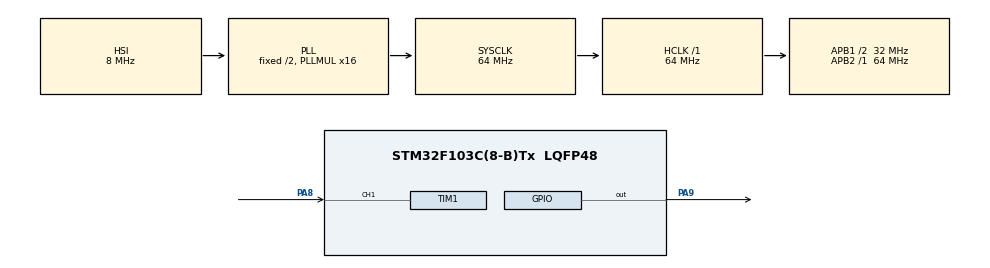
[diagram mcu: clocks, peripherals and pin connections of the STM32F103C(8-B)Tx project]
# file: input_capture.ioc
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Mcu.Family=STM32F1
Mcu.Name=STM32F103C(8-B)Tx
Mcu.Package=LQFP48
NVIC.PriorityGroup=NVIC_PRIORITYGROUP_4
NVIC.TIM1_CC_IRQn=true\:3\:0\:true\:false\:true\:true\:true\:true
PA13.Mode=Serial_Wire
PA13.Signal=SYS_JTMS-SWDIO
PA14.Mode=Serial_Wire
PA14.Signal=SYS_JTCK-SWCLK
PA8.Signal=S_TIM1_CH1
PA9.Signal=GPIO_Output
ProjectManager.HeapSize=0x200
ProjectManager.StackSize=0x400
ProjectManager.TargetToolchain=STM32CubeIDE
RCC.AHBFreq_Value=64000000
RCC.APB1CLKDivider=RCC_HCLK_DIV2
RCC.APB1Freq_Value=32000000
RCC.APB1TimFreq_Value=64000000
RCC.APB2Freq_Value=64000000
RCC.APB2TimFreq_Value=64000000
RCC.HCLKFreq_Value=64000000
RCC.PLLMUL=RCC_PLL_MUL16
RCC.SYSCLKFreq_VALUE=64000000
RCC.SYSCLKSource=RCC_SYSCLKSOURCE_PLLCLK
RCC.USBFreq_Value=64000000
SH.S_TIM1_CH1.0=TIM1_CH1,Input_Capture1_from_TI1
TIM1.Channel-Input_Capture1_from_TI1=TIM_CHANNEL_1
TIM1.Prescaler=63
VP_TIM1_VS_ClockSourceINT.Mode=Internal
board=custom

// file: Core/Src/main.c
/* USER CODE BEGIN Header */
/**
  ******************************************************************************
  * @file           : main.c
  * @brief          : Main program body
  ******************************************************************************
  * @attention
  *
  * Copyright (c) 2026 STMicroelectronics.
  * All rights reserved.
  *
  * This software is licensed under terms that can be found in the LICENSE file
  * in the root directory of this software component.
  * If no LICENSE file comes with this software, it is provided AS-IS.
  *
  ******************************************************************************
  */
/* USER CODE END Header */
#include "main.h"

/* USER CODE BEGIN Includes */
#include "hcsr04.h"
/* USER CODE END Includes */

TIM_HandleTypeDef htim1;

/* USER CODE BEGIN PV */

HCSR04_Cliff_t my_hcsr04_1;
HCSR04_Cliff_t my_hcsr04_2;

volatile float debug_dist_1 = 0.0f;
volatile float debug_dist_2 = 0.0f;
volatile uint8_t filter_1 = 0;
volatile uint8_t filter_2 = 0;

volatile uint8_t flag_cliff_1 = 0;
volatile uint8_t flag_cliff_2 = 0;

uint32_t last_ping_time = 0;
uint8_t current_sensor = 1;

/* USER CODE END PV */

void SystemClock_Config(void);
static void MX_GPIO_Init(void);
static void MX_TIM1_Init(void);

/* USER CODE BEGIN 0 */
void Callback_Sensor1(HCSR04_Cliff_t* dev) {
    flag_cliff_1 = 1;
}

void Callback_Sensor2(HCSR04_Cliff_t* dev) {
    flag_cliff_2 = 1;
}

void HAL_TIM_IC_CaptureCallback(TIM_HandleTypeDef *htim)
{
    if (htim->Instance == TIM1)
    {
        // Truyền thẳng cả 2 vào, code trong hcsr04.c của bạn
        // sẽ tự biết lọc cái nào của CH1, cái nào của CH2
        HCSR04_Cliff_Capture_Callback(&my_hcsr04_1, htim);
        HCSR04_Cliff_Capture_Callback(&my_hcsr04_2, htim);
    }
}

/* USER CODE END 0 */

int main(void)
{

  /* MCU Configuration--------------------------------------------------------*/

  /* Reset of all peripherals, Initializes the Flash interface and the Systick. */
  HAL_Init();

  /* Configure the system clock */
  SystemClock_Config();

  /* Initialize all configured peripherals */
  MX_GPIO_Init();
  MX_TIM1_Init();
  /* USER CODE BEGIN 2 */

  /* QUAN TRỌNG - kiểm tra trong file .ioc:
   *  - Pinout: PA8 phải được gán là TIM1_CH1 (Input Capture direct mode).
   *            ECHO của HC-SR04 phải nối vào PA8, KHÔNG phải PA9.
   *            PA9 chỉ dùng làm chân TRIG (GPIO output).
   *  - NVIC  : tick "TIM1 capture compare interrupt" (TIM1_CC_IRQn).
   * Dòng enable NVIC dưới đây là lớp phòng hộ bằng code, để ngắt vẫn
   * chạy được dù lỡ quên tick trong .ioc. Nhưng việc gán PA8 = TIM1_CH1
   * thì PHẢI làm trong .ioc, code không thay được phần đó. */
  HAL_NVIC_SetPriority(TIM1_CC_IRQn, 0, 0);
  HAL_NVIC_EnableIRQ(TIM1_CC_IRQn);

  /* USER CODE BEGIN 2 */
    // Init Sensor 1 (TRIG = PB0, ECHO = PA8/CH1)
    HCSR04_Cliff_Init(&my_hcsr04_1, GPIOB, GPIO_PIN_0, &htim1, TIM_CHANNEL_1, 10.0f, Callback_Sensor1);

    // Init Sensor 2 (TRIG = PB1, ECHO = PA9/CH2)
    HCSR04_Cliff_Init(&my_hcsr04_2, GPIOB, GPIO_PIN_1, &htim1, TIM_CHANNEL_2, 10.0f, Callback_Sensor2);

    // Tắt LED mặc định ban đầu
    HAL_GPIO_WritePin(GPIOC, GPIO_PIN_13, GPIO_PIN_SET);
    /* USER CODE END 2 */

  /* Infinite loop */
  /* USER CODE BEGIN WHILE */
  while (1)
  {
	  if (HAL_GetTick() - last_ping_time > 50)
	        {
	            if (current_sensor == 1 && my_hcsr04_1.state == HCSR04_IDLE_STATE) {
	                HCSR04_Cliff_Start(&my_hcsr04_1);
	                current_sensor = 2; // Nhường lượt tiếp theo cho con 2
	                last_ping_time = HAL_GetTick();
	            }
	            else if (current_sensor == 2 && my_hcsr04_2.state == HCSR04_IDLE_STATE) {
	                HCSR04_Cliff_Start(&my_hcsr04_2);
	                current_sensor = 1; // Nhường lượt tiếp theo cho con 1
	                last_ping_time = HAL_GetTick();
	            }
	        }

	        // 2. GIÁM SÁT LIÊN TỤC (Xử lý khoảng cách hoặc Timeout)
	        HCSR04_Cliff_Handle(&my_hcsr04_1);
	        HCSR04_Cliff_Handle(&my_hcsr04_2);

	        // 3. CẬP NHẬT BIẾN DEBUG
	        debug_dist_1 = my_hcsr04_1.distance;
	        debug_dist_2 = my_hcsr04_2.distance;
	        filter_1 = my_hcsr04_1.filter_count;
	        filter_2 = my_hcsr04_2.filter_count;

	        // 4. XỬ LÝ CẢNH BÁO LED CHUNG
	        // (Ví dụ: 1 trong 2 con phát hiện hố sâu < 10cm thì bật LED)
	        if (flag_cliff_1 == 1 || flag_cliff_2 == 1)
	        {
	            HAL_GPIO_WritePin(GPIOC, GPIO_PIN_13, GPIO_PIN_RESET); // Bật LED
	            flag_cliff_1 = 0;
	            flag_cliff_2 = 0;
	        }
	        else if (my_hcsr04_1.filter_count == 0 && my_hcsr04_2.filter_count == 0)
	        {
	            HAL_GPIO_WritePin(GPIOC, GPIO_PIN_13, GPIO_PIN_SET); // Tắt LED khi CẢ HAI an toàn
	        }

	        HAL_Delay(1);
    /* USER CODE END WHILE */

  }
}

void SystemClock_Config(void)
{
  RCC_OscInitTypeDef RCC_OscInitStruct = {0};
  RCC_ClkInitTypeDef RCC_ClkInitStruct = {0};

  /** Initializes the RCC Oscillators according to the specified parameters
  * in the RCC_OscInitTypeDef structure.
  */
  RCC_OscInitStruct.OscillatorType = RCC_OSCILLATORTYPE_HSI;
  RCC_OscInitStruct.HSIState = RCC_HSI_ON;
  RCC_OscInitStruct.HSICalibrationValue = RCC_HSICALIBRATION_DEFAULT;
  RCC_OscInitStruct.PLL.PLLState = RCC_PLL_ON;
  RCC_OscInitStruct.PLL.PLLSource = RCC_PLLSOURCE_HSI_DIV2;
  RCC_OscInitStruct.PLL.PLLMUL = RCC_PLL_MUL16;
  if (HAL_RCC_OscConfig(&RCC_OscInitStruct) != HAL_OK)
  {
    Error_Handler();
  }

  /** Initializes the CPU, AHB and APB buses clocks
  */
  RCC_ClkInitStruct.ClockType = RCC_CLOCKTYPE_HCLK|RCC_CLOCKTYPE_SYSCLK
                              |RCC_CLOCKTYPE_PCLK1|RCC_CLOCKTYPE_PCLK2;
  RCC_ClkInitStruct.SYSCLKSource = RCC_SYSCLKSOURCE_PLLCLK;
  RCC_ClkInitStruct.AHBCLKDivider = RCC_SYSCLK_DIV1;
  RCC_ClkInitStruct.APB1CLKDivider = RCC_HCLK_DIV2;
  RCC_ClkInitStruct.APB2CLKDivider = RCC_HCLK_DIV1;

  if (HAL_RCC_ClockConfig(&RCC_ClkInitStruct, FLASH_LATENCY_2) != HAL_OK)
  {
    Error_Handler();
  }
}

static void MX_TIM1_Init(void)
{

  TIM_MasterConfigTypeDef sMasterConfig = {0};
  TIM_IC_InitTypeDef sConfigIC = {0};

  htim1.Instance = TIM1;
  htim1.Init.Prescaler = 63;
  htim1.Init.CounterMode = TIM_COUNTERMODE_UP;
  htim1.Init.Period = 65535;
  htim1.Init.ClockDivision = TIM_CLOCKDIVISION_DIV1;
  htim1.Init.RepetitionCounter = 0;
  htim1.Init.AutoReloadPreload = TIM_AUTORELOAD_PRELOAD_DISABLE;
  if (HAL_TIM_IC_Init(&htim1) != HAL_OK)
  {
    Error_Handler();
  }
  sMasterConfig.MasterOutputTrigger = TIM_TRGO_RESET;
  sMasterConfig.MasterSlaveMode = TIM_MASTERSLAVEMODE_DISABLE;
  if (HAL_TIMEx_MasterConfigSynchronization(&htim1, &sMasterConfig) != HAL_OK)
  {
    Error_Handler();
  }
  sConfigIC.ICPolarity = TIM_INPUTCHANNELPOLARITY_RISING;
  sConfigIC.ICSelection = TIM_ICSELECTION_DIRECTTI;
  sConfigIC.ICPrescaler = TIM_ICPSC_DIV1;
  sConfigIC.ICFilter = 0;
  if (HAL_TIM_IC_ConfigChannel(&htim1, &sConfigIC, TIM_CHANNEL_1) != HAL_OK)
  {
    Error_Handler();
  }
  if (HAL_TIM_IC_ConfigChannel(&htim1, &sConfigIC, TIM_CHANNEL_2) != HAL_OK)
  {
    Error_Handler();
  }

}

static void MX_GPIO_Init(void)
{
  GPIO_InitTypeDef GPIO_InitStruct = {0};

  /* GPIO Ports Clock Enable */
  __HAL_RCC_GPIOC_CLK_ENABLE();
  __HAL_RCC_GPIOB_CLK_ENABLE();
  __HAL_RCC_GPIOA_CLK_ENABLE();

  /*Configure GPIO pin Output Level */
  HAL_GPIO_WritePin(GPIOC, GPIO_PIN_13, GPIO_PIN_RESET);

  /*Configure GPIO pin Output Level */
  HAL_GPIO_WritePin(GPIOB, GPIO_PIN_0|GPIO_PIN_1, GPIO_PIN_RESET);

  /*Configure GPIO pin : PC13 */
  GPIO_InitStruct.Pin = GPIO_PIN_13;
  GPIO_InitStruct.Mode = GPIO_MODE_OUTPUT_PP;
  GPIO_InitStruct.Pull = GPIO_NOPULL;
  GPIO_InitStruct.Speed = GPIO_SPEED_FREQ_LOW;
  HAL_GPIO_Init(GPIOC, &GPIO_InitStruct);

  /*Configure GPIO pins : PB0 PB1 */
  GPIO_InitStruct.Pin = GPIO_PIN_0|GPIO_PIN_1;
  GPIO_InitStruct.Mode = GPIO_MODE_OUTPUT_PP;
  GPIO_InitStruct.Pull = GPIO_NOPULL;
  GPIO_InitStruct.Speed = GPIO_SPEED_FREQ_LOW;
  HAL_GPIO_Init(GPIOB, &GPIO_InitStruct);

}

void Error_Handler(void)
{
  __disable_irq();
  while (1)
  {
  }
}
